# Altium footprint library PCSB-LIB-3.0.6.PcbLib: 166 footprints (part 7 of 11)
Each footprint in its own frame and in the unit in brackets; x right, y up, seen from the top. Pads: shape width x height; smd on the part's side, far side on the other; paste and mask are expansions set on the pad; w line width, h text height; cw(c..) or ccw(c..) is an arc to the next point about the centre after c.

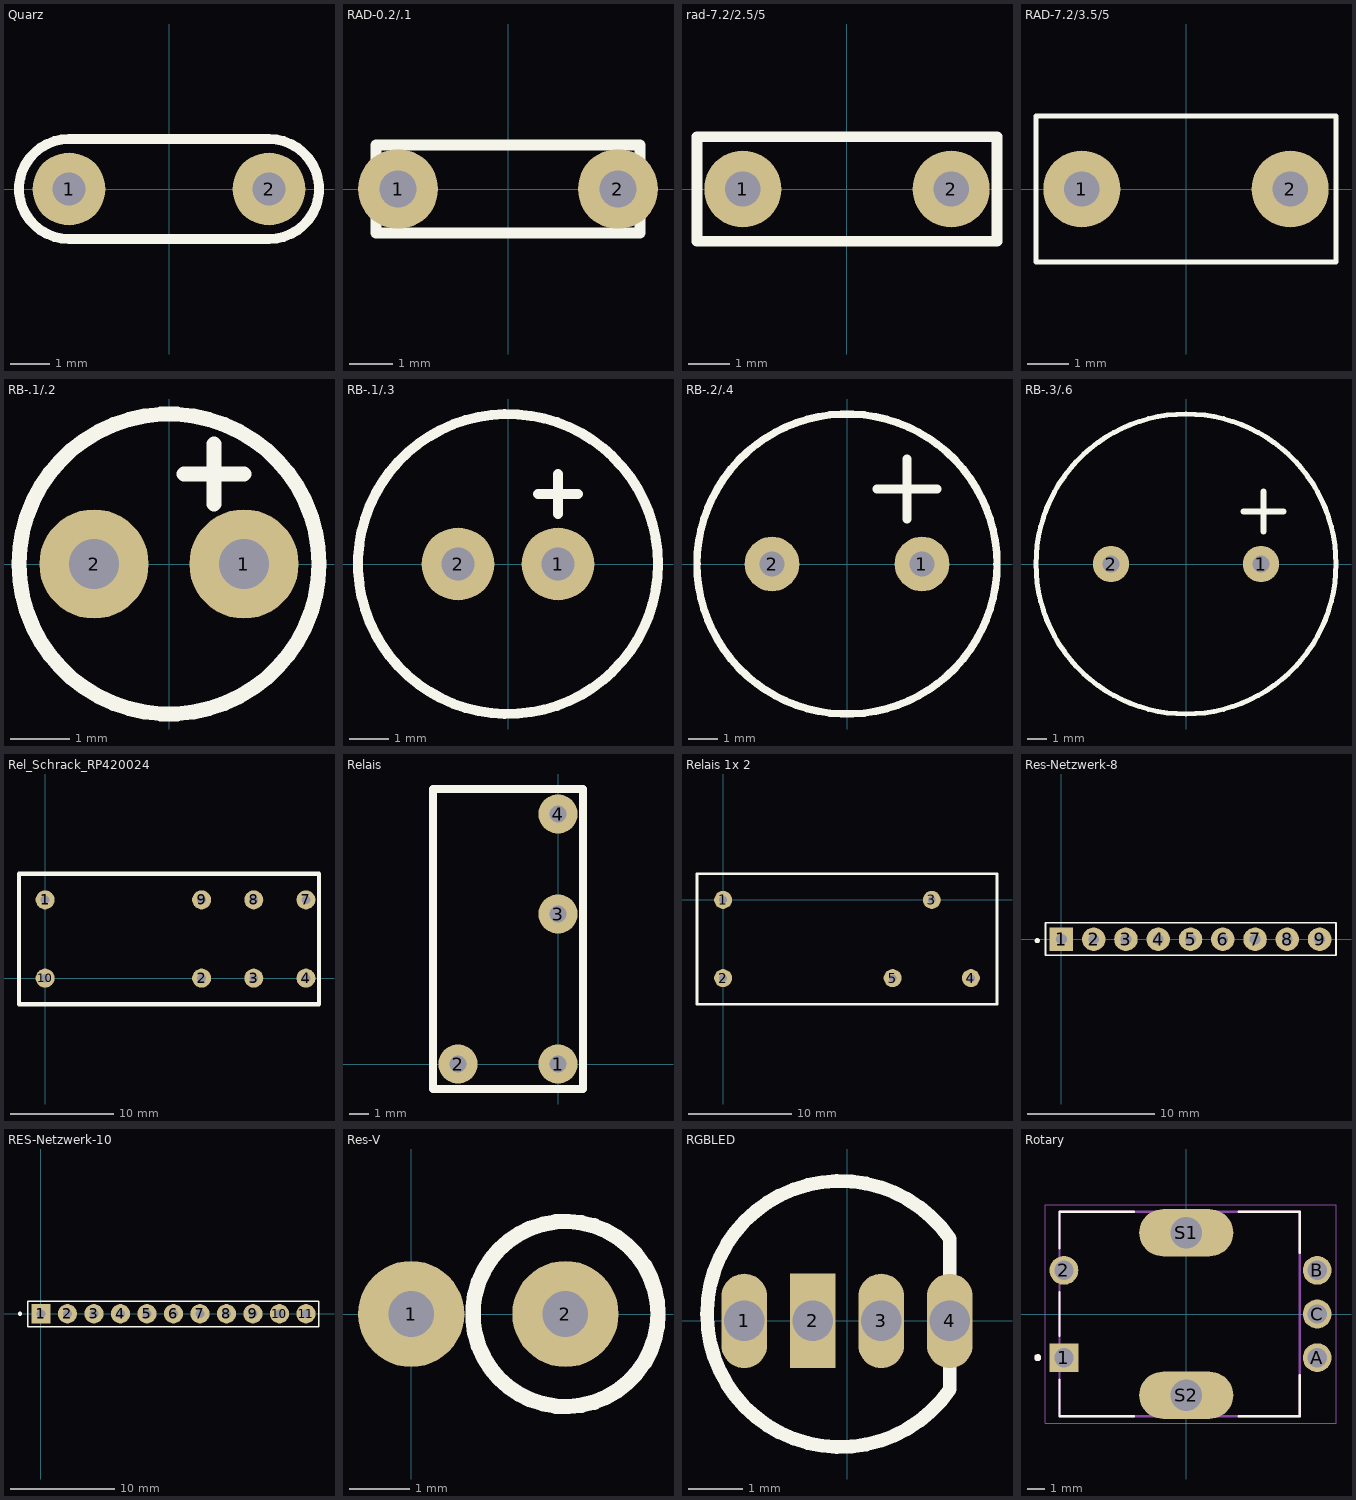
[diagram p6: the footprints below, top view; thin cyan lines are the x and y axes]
## Quarz [mm]
pads (2):
  round 1.85 hole 0.85: 1(-2.54,0) 2(2.54,0)
Top Overlay:
  lines w0.254: -2.54,-1.27 cw(c-2.54,0) -2.54,1.27 2.54,1.27 cw(c2.54,0) 2.54,-1.27 -2.54,-1.27

## RAD-0.2/.1 [mm]
pads (2):
  round 1.85 hole 0.85: 1(-2.54,0) 2(2.54,0)
Top Overlay:
  lines w0.254: -3.048,-1.016 3.048,-1.016 3.048,1.016 -3.048,1.016 -3.048,-1.016

## rad-7.2/2.5/5 [mm]
pads (2):
  round 1.85 hole 0.85: 1(-2.5,0) 2(2.5,0)
Top Overlay:
  lines w0.254: -3.6,-1.25 3.6,-1.25 3.6,1.25 -3.6,1.25 -3.6,-1.25

## RAD-7.2/3.5/5 [mm]
pads (2):
  round 1.85 hole 0.85: 1(-2.5,0) 2(2.5,0)
Top Overlay:
  lines w0.127: -3.6,-1.75 3.6,-1.75 3.6,1.75 -3.6,1.75 -3.6,-1.75

## RB-.1/.2 [mm]
pads (2):
  round 1.85 hole 0.85: 1(1.27,0) 2(-1.27,0)
Top Overlay:
  circle w0.254: c0,0 r2.54
  lines w0.254: 0.254,1.524 1.27,1.524 ; 0.762,1.016 0.762,2.032

## RB-.1/.3 [mm]
pads (2):
  round 1.85 hole 0.85: 1(1.27,0) 2(-1.27,0)
Top Overlay:
  circle w0.254: c0,0 r3.81
  lines w0.254: 0.762,1.778 1.778,1.778 ; 1.27,1.27 1.27,2.286

## RB-.2/.4 [mm]
pads (2):
  round 1.85 hole 0.85: 1(2.54,0) 2(-2.54,0)
Top Overlay:
  circle w0.254: c0,0 r5.08
  lines w0.305: 1.016,2.54 3.048,2.54 ; 2.032,1.524 2.032,3.556

## RB-.3/.6 [mm]
pads (2):
  round 1.85 hole 0.85: 1(3.81,0) 2(-3.81,0)
Top Overlay:
  circle w0.254: c0,0 r7.62
  lines w0.305: 2.921,2.667 3.429,2.667 4.445,2.667 4.953,2.667 ; 3.937,1.651 3.937,2.159 3.937,3.175 3.937,3.683

## Rel_Schrack_RP420024 [mm] "24V; 2 Wechselkontakte 250V/8A"
height 25
pads (8):
  round 1.85 hole 0.85: 1(0,7.62) 2(15.24,0) 3(20.32,0) 4(25.4,0) 7(25.4,7.62) 8(20.32,7.62) 9(15.24,7.62) 10(0,0)
Top Overlay:
  lines w0.4: -2.54,-2.54 26.67,-2.54 26.67,10.16 25.4,10.16 -2.54,10.16 -2.54,-2.54

## Relais [mm] "K?"
pads (4):
  round 2 hole 0.85: 1(0,0) 2(-5.08,0) 3(0,7.62) 4(0,12.7)
Top Overlay:
  lines w0.4: -6.35,-1.27 -6.35,13.97 1.27,13.97 1.27,-1.27 -6.35,-1.27

## Relais 1x 2 [mm]
pads (5):
  round 1.75 hole 0.75: 1(0,0) 2(0,-7.62) 3(20.32,0) 4(24.13,-7.62) 5(16.51,-7.62)
Top Overlay:
  lines w0.254: -2.54,-10.16 -2.54,2.54 26.67,2.54 26.67,-10.16 -2.54,-10.16

## Res-Netzwerk-8 [mm]
height 5.08
pads (9):
  rect 1.85x1.85 hole 0.85: 1(0,0)
  round 1.85 hole 0.85: 2(2.54,0) 3(5.08,0) 4(7.62,0) 5(10.16,0) 6(12.7,0) 7(15.24,0) 8(17.78,0) 9(20.32,0)
Top Overlay:
  circle w0.2: c-1.9,-0.1 r0.1
  lines w0.127: -1.25,-1.25 -1.25,1.3 21.61,1.3 21.61,-1.25 -1.25,-1.25

## RES-Netzwerk-10 [mm]
height 5.08
pads (11):
  rect 1.85x1.85 hole 0.85: 1(0,0)
  round 1.85 hole 0.85: 2(2.54,0) 3(5.08,0) 4(7.62,0) 5(10.16,0) 6(12.7,0) 7(15.24,0) 8(17.78,0) 9(20.32,0) 10(22.86,0) 11(25.4,0)
Top Overlay:
  circle w0.2: c-2,0 r0.1
  lines w0.127: -1.25,-1.25 26.65,-1.25 26.65,1.2 -1.25,1.2 -1.25,-1.25

## Res-V [mm]
pads (2):
  round 1.75 hole 0.75: 1(0,0) 2(2.54,0)
Top Overlay:
  circle w0.254: c2.54,0 r1.524

## RGBLED [mm]
pads (4):
  oval 0.85x1.75 hole 0.75: 1(-1.905,0) 3(0.635,0) 4(1.905,0)
  rect 0.85x1.75 hole 0.75: 2(-0.635,0)
Top Overlay:
  lines w0.254: 1.905,-0.635 1.905,-1.27 cw(c-0.127,0.127) 1.905,1.524 1.905,0.635

## Rotary [mm]
pads (7):
  rect 1.65x1.65 hole 1.1: 1(-7,-2.5)
  round 1.65 hole 1.1: 2(-7,2.5) A(7.5,-2.5) B(7.5,2.5) C(7.5,0)
  oval 5.4x2.7 hole 1.8: S1(0,4.65) S2(0,-4.65)
Top Overlay:
  circle w0.2: c-8.5,-2.5 r0.1
  lines w0.127: -7.25,-3.75 -7.25,-5.85 -3,-5.85 ; -7.25,-1.25 -7.25,1.25 ; -7.25,3.75 -7.25,5.85 -3,5.85 ; 3,-5.85 6.5,-5.85 6.5,-3.5 ; 3,5.85 6.5,5.85 6.5,3.5
Mechanical 1:
  lines w0: -1.35,-5.6 1.35,-5.6 1.35,-3.7 -1.35,-3.7 -1.35,-5.6 ; -1.35,3.7 1.35,3.7 1.35,5.6 -1.35,5.6 -1.35,3.7
Mechanical 13:
  circle w0.2: c-8.5,-2.5 r0.1
  lines w0.127: -7.25,-5.85 6.5,-5.85 6.5,5.85 -7.25,5.85 -7.25,-5.85
Mechanical 15:
  lines w0.05: -8.075,-6.25 8.575,-6.25 8.575,6.25 -8.075,6.25 -8.075,-6.25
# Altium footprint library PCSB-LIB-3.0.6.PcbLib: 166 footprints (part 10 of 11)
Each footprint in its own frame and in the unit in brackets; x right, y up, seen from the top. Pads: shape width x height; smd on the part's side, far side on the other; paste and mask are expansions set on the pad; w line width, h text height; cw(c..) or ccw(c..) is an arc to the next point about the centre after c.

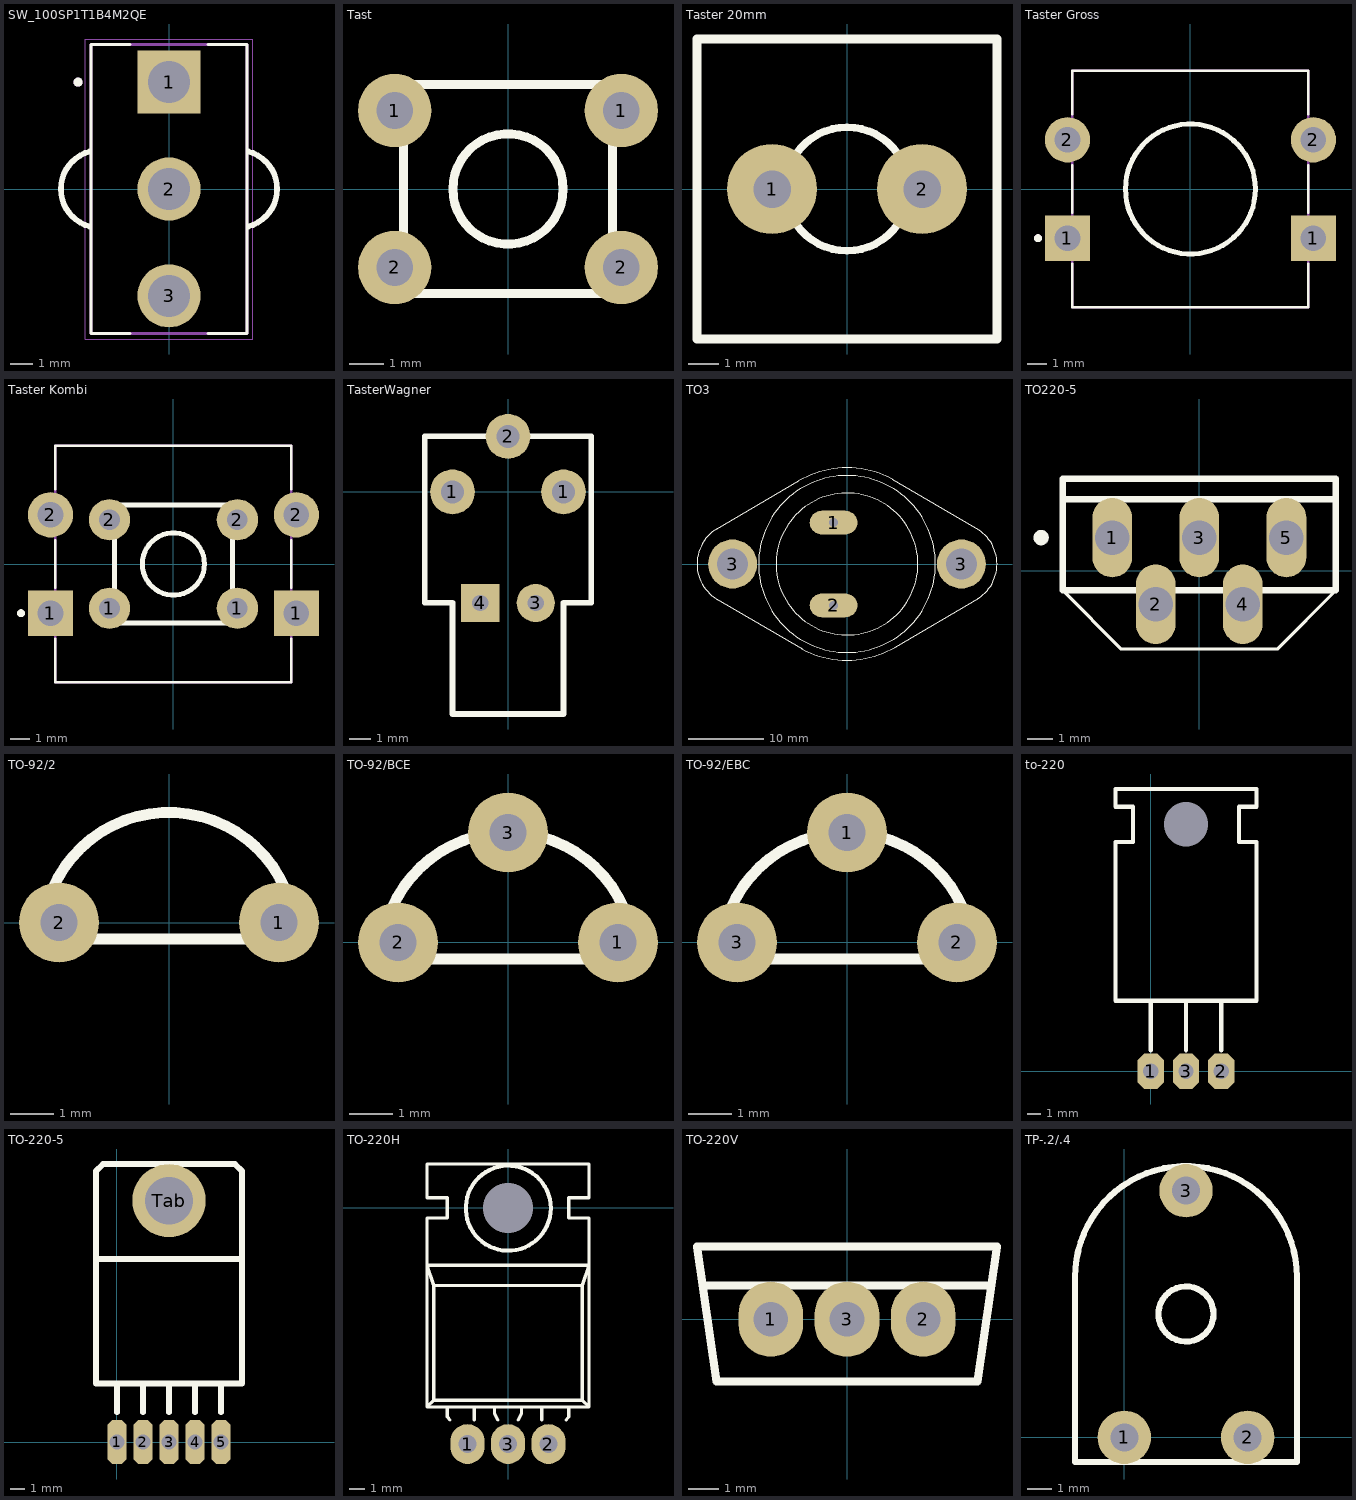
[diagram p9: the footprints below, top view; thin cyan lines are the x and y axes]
## SW_100SP1T1B4M2QE [mm]
pads (3):
  rect 2.775x2.775 hole 1.85: 1(0,4.7)
  round 2.775 hole 1.85: 2(0,0) 3(0,-4.7)
Top Overlay:
  circle w0.2: c-4,4.7 r0.1
  lines w0.127: -1.71,-6.35 -3.43,-6.35 -3.43,6.35 -1.71,6.35 ; 1.71,-6.35 3.43,-6.35 3.43,6.35 1.71,6.35
  lines w0.254: -3.49,-1.65 cw(c-3.048,0) -3.49,1.65 ; 3.49,-1.65 ccw(c3.048,0) 3.49,1.65
Mechanical 13:
  circle w0.2: c-4,4.7 r0.1
  lines w0.127: -3.43,-6.35 -3.43,6.35 3.43,6.35 3.43,-6.35 -3.43,-6.35
Mechanical 15:
  lines w0.05: -3.68,-6.6 -3.68,6.6 3.68,6.6 3.68,-6.6 -3.68,-6.6

## Tast [mm]
pads (4):
  round 2.1 hole 1.05: 1(-3.25,2.25) 1(3.25,2.25) 2(-3.25,-2.25) 2(3.25,-2.25)
Top Overlay:
  circle w0.254: c0,0 r1.581
  lines w0.254: -3,-3 3,-3 3,3 -3,3 -3,-3

## Taster 20mm [mm]
height 20
pads (2):
  round 3 hole 1.25 unplated: 1(-2.5,0) 2(2.5,0)
Top Overlay:
  circle w0.254: c0,0 r2.062
  lines w0.3: -5,-5 -5,5 5,5 5,-5 -5,-5

## Taster Gross [mm]
height 7.8
pads (4):
  rect 2.3x2.3 hole 1.3: 1(-6.25,-2.5) 1(6.25,-2.5)
  round 2.3 hole 1.3: 2(-6.25,2.5) 2(6.25,2.5)
Top Overlay:
  circle w0.254: c0,0 r3.302
  circle w0.2: c-7.75,-2.5 r0.1
  lines w0.127: -6,-3.788 -6,-6 6,-6 6,-3.788 ; -6,-1.212 -6,1.212 ; -6,3.788 -6,6 6,6 6,3.788 ; 6,-1.212 6,1.212
Mechanical 13:
  circle w0.2: c-7.75,-2.5 r0.1
  lines w0.127: -6,-6 6,-6 6,6 -6,6 -6,-6

## Taster Kombi [mm]
height 7.8
pads (8):
  rect 2.3x2.3 hole 1.3: 1(-6.25,-2.5) 1(6.25,-2.5)
  round 2.1 hole 1.05: 1(-3.25,-2.25) 1(3.25,-2.25) 2(-3.25,2.25) 2(3.25,2.25)
  round 2.3 hole 1.3: 2(-6.25,2.5) 2(6.25,2.5)
Top Overlay:
  circle w0.2: c-7.75,-2.5 r0.1
  circle w0.254: c0,0 r1.581
  lines w0.127: -6,-3.788 -6,-6 6,-6 6,-3.788 ; -6,-1.212 -6,1.212 ; -6,3.788 -6,6 6,6 6,3.788 ; 6,-1.212 6,1.212
  lines w0.254: -3,-3 -3,3 3,3 3,-3 -3,-3
Mechanical 13:
  lines w0.127: -6,-6 -6,6 6,6 6,-6 -6,-6

## TasterWagner [mm]
pads (5):
  round 2.05 hole 1.05: 1(-2.54,0) 1(2.54,0) 2(0,2.54)
  round 1.75 hole 0.75: 3(1.27,-5.08)
  rect 1.75x1.75 hole 0.75: 4(-1.27,-5.08)
Top Overlay:
  lines w0.254: -3.81,-5.08 -2.54,-5.08 -2.54,-10.16 1.905,-10.16 2.54,-10.16 2.54,-5.08 3.81,-5.08 3.81,2.54 -3.81,2.54 -3.81,-5.08

## TO3 [mil]
pads (4):
  oval 248x124 hole 47.05: 1(-70,215) 2(-70,-215)
  round 255 hole 162: 3(-595,0) 3(595,0)
Top Overlay:
  circle w6: c0,0 r369
  circle w2: c0,0 r460
  lines w6: -680,180 -250,433 cw(c0,0) 0,500 cw(c0,0) 234.74,441.47 ; -679,-181 -234,-442 ; -676.7,-182.58 cw(c-567,0) -780,0 cw(c-567,0) -673.5,184.46 ; -234.74,-441.47 ccw(c0,0) 0,-500 ccw(c0,0) 250,-433.01 ; 235,441 684,178 ; 251,-433 684,-178 ; 683.01,-178.64 ccw(c567,0) 780,0 ccw(c567,0) 683.01,178.64
Mechanical 13:
  circle w6: c595,0 r85
  circle w6: c-595,0 r85

## TO220-5 [mm]
height 16.51
pads (5):
  oval 1.55x3.1 hole 1.35: 1(-3.4,1.3) 2(-1.7,-1.3) 3(0,1.3) 4(1.7,-1.3) 5(3.4,1.3)
Top Overlay:
  circle w0.2: c-6.175,1.3 r0.2
  rectangle: -6.325,1.15 -5.975,1.5
  lines w0.127: -5.335,-0.761 -5.335,3.59 5.335,3.59 5.335,-0.761 3.048,-3.048 -3.048,-3.048 -5.335,-0.761
  lines w0.254: -5.334,2.794 5.334,2.794 ; 5.334,2.794 5.334,3.589 5.333,3.59 -5.335,3.59 -5.334,3.589 -5.334,-0.762 5.334,-0.762 5.334,2.794

## TO-92/2 [mm]
pads (2):
  round 1.85 hole 0.85: 1(2.54,0) 2(-2.54,0)
Top Overlay:
  lines w0.254: -2.927,-0.381 cw(c-0.003,-0.381) 2.921,-0.381 -2.927,-0.381

## TO-92/BCE [mm]
pads (3):
  round 1.85 hole 0.85: 1(2.54,0) 2(-2.54,0) 3(0,2.54)
Top Overlay:
  lines w0.254: -2.927,-0.381 cw(c-0.003,-0.381) 2.921,-0.381 -2.927,-0.381

## TO-92/EBC [mm] "Standard-Transistor wie BC546"
pads (3):
  round 1.85 hole 0.85: 1(0,2.54) 2(2.54,0) 3(-2.54,0)
Top Overlay:
  lines w0.254: -2.927,-0.381 cw(c-0.003,-0.381) 2.921,-0.381 -2.927,-0.381

## to-220 [mm]
pads (4):
  round 0 hole 3.2 unplated: 0(2.537,17.788)
  oct 1.905x2.54 hole 1.1: 1(-0.003,0.008) 2(5.077,0.008) 3(2.537,0.008)
Top Overlay:
  lines w0.305: -0.003,1.532 -0.003,5.088 ; 2.537,1.532 2.537,5.088 ; 5.077,1.532 5.077,5.088 ; -2.543,5.088 7.617,5.088 7.617,16.518 6.347,16.518 6.347,19.058 7.617,19.058 7.617,20.328 -2.543,20.328 -2.543,19.058 -1.273,19.058 -1.273,16.518 -2.543,16.518 -2.543,5.088

## TO-220-5 [mm]
height 5
pads (6):
  oct 1.3x3 hole 1.05: 1(0,0) 2(1.778,0) 3(3.556,0) 4(5.334,0) 5(7.112,0)
  round 5 hole 3.25: Tab(3.556,16.5)
Top Overlay:
  lines w0.4: 0,2.032 0,4 ; 1.778,2.032 1.778,4 ; 3.556,2.032 3.556,4 ; 3.556,16.5 3.556,19 ; 5.334,2.032 5.334,4 ; 7.112,2.032 7.112,4 ; -1.444,12.5 -1.444,18.5 -0.944,19 8.056,19 8.556,18.5 ; -1.444,12.5 -1.444,4 8.556,4 8.556,12.5 ; -1.444,12.5 8.556,12.5 ; 8.556,12.5 8.556,18.5 ; 8.556,18.5 8.556,18.5

## TO-220H [mm]
pads (4):
  round 0 hole 3.15: 0(0,0)
  oval 2.15x2.5 hole 1.15: 1(-2.54,-14.817) 2(2.54,-14.817) 3(0,-14.817)
Top Overlay:
  circle w0.254: c0.017,-0.02 r2.667
  lines w0.2: -3.81,-13.123 -3.81,-12.488 ; -3.762,-13.155 -3.647,-13.317 ; -2.117,-13.317 -2.117,-12.488 ; -0.847,-12.488 -0.847,-12.912 -0.635,-13.317 ; 0.635,-13.317 0.847,-12.912 0.847,-12.488 ; 2.117,-13.317 2.117,-12.488 ; 3.655,-13.317 3.818,-13.099 ; 3.81,-13.123 3.81,-12.488 ; -5.08,-12.488 -4.657,-12.065 ; -5.08,-12.488 5.08,-12.488 ; -5.08,-12.488 -5.08,-0.635 -3.81,-0.635 -3.81,0.635 -5.08,0.635 -5.08,2.752 5.08,2.752 5.08,0.635 3.81,0.635 3.81,-0.635 5.08,-0.635 5.08,-12.488 ; -4.657,-12.065 4.657,-12.065 ; -4.657,-12.065 -4.657,-4.868 ; -4.657,-4.868 4.657,-4.868 ; -4.657,-4.868 -5.08,-3.598 5.08,-3.598 4.657,-4.868 ; 4.657,-12.065 5.08,-12.488 ; 4.657,-12.065 4.657,-4.868

## TO-220V [mm]
pads (3):
  oval 2.15x2.5 hole 1.15: 1(-2.54,0) 2(2.54,0) 3(0,0)
Top Overlay:
  lines w0.254: -4.812,1.125 4.808,1.125 ; -5,2.425 -4.35,-2.075 0,-2.075 4.35,-2.075 5,2.425 0,2.425 -5,2.425

## TP-.2/.4 [mm] "Trimpotentiometer liegend klein"
pads (3):
  round 2.2 hole 1.15: 1(0,0) 2(5.08,0) 3(2.54,10.16)
Top Overlay:
  circle w0.254: c2.54,5.08 r1.136
  lines w0.254: -2.032,-1.016 7.112,-1.016 7.112,6.604 ccw(c2.54,6.604) -2.032,6.604 -2.032,-1.016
